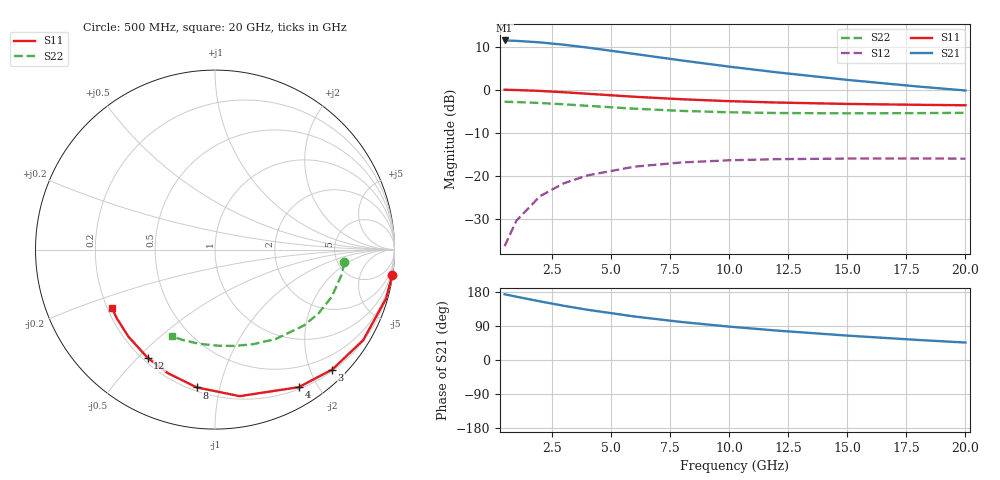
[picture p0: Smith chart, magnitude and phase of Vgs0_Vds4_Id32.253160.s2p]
# Hz S RI R 50
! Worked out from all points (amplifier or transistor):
!   12 points, 500 MHz to 20 GHz, reference 50 ohm
!   highest |S21| = 11.4 dB at 500 MHz (marker M1)
!   |S21| within 3 dB of that: start of sweep to 5.825 GHz
!   unconditionally stable (mu >= 1): 17.68 GHz to end of sweep
!   at 2 GHz: K = 0.10, MSG = 17.8 dB, |S12| = -24.7 dB
!   at 8 GHz: K = 0.42, MSG = 11.8 dB, |S12| = -16.9 dB
!   at 20 GHz: K = 1.15, MAG = 5.5 dB, |S12| = -16.0 dB
!   S11 on the Smith chart (normalised r, x): 500 MHz: 0, -14; 3 GHz: 0.22, -2.36; 4 GHz: 0.22, -1.76; 8 GHz: 0.22, -0.85; 12 GHz: 0.22, -0.53; 20 GHz: 0.22, -0.25
5e8  0.988 -0.1397  -3.7 0.4217  0.00147 0.0153  0.7205 -0.0709
1e9  0.9529 -0.2735  -3.59 0.8246  0.00576 0.0298  0.7055 -0.1394
2e9  0.8259 -0.5042  -3.195 1.514  0.0212 0.0542  0.6512 -0.2614
3e9  0.6527 -0.6686  -2.659 1.995  0.0422 0.0704  0.5759 -0.3565
4e9  0.4669 -0.7664  -2.087 2.267  0.0644 0.0783  0.4931 -0.4243
6e9  0.1373 -0.8166  -1.087 2.358  0.1028 0.0764  0.3376 -0.4984
8e9  -0.1018 -0.7678  -0.3872 2.148  0.1289 0.0627  0.2103 -0.5274
1e10  -0.2644 -0.6874  0.0608 1.851  0.1447 0.0461  0.1074 -0.5364
1.2e10  -0.3752 -0.6028  0.3386 1.556  0.1535 0.0299  0.021 -0.536
1.5e10  -0.4819 -0.4855  0.5625 1.172  0.1589 0.00867  -0.0891 -0.5246
1.8e10  -0.5466 -0.3837  0.6565 0.8681  0.1591 -0.00858  -0.1831 -0.5029
2e10  -0.5754 -0.3234  0.6793 0.7047  0.1577 -0.0182  -0.2386 -0.4834
